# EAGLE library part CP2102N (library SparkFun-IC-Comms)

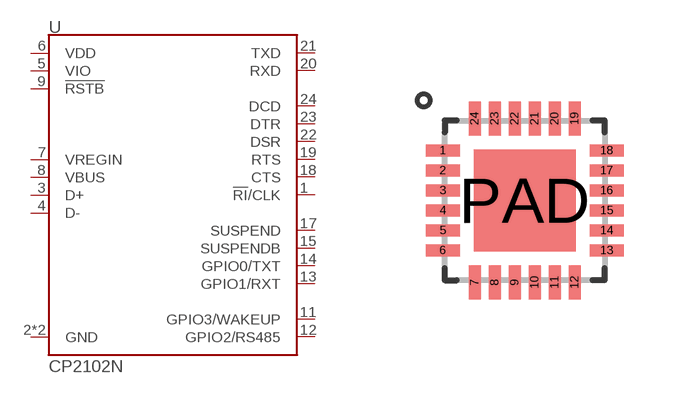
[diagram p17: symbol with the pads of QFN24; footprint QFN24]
Designator prefix U

## CP2102N (PROD_ID: IC-14020)  [QFN24]
1  !RI!/CLK
2  GND
3  D+
4  D-
5  VIO
6  VDD
7  VREGIN
8  VBUS
9  !RSTB
11  GPIO3/WAKEUP
12  GPIO2/RS485
13  GPIO1/RXT
14  GPIO0/TXT
15  SUSPENDB
17  SUSPEND
18  CTS
19  RTS
20  RXD
21  TXD
22  DSR
23  DTR
24  DCD
PAD  GND

## Footprint QFN24 (pad centres in mm)
QFN24 Package
smd 0.85 x 0.3: 1 -2.05,1.25; 2 -2.05,0.75; 3 -2.05,0.25; 4 -2.05,-0.25; 5 -2.05,-0.75; 6 -2.05,-1.25; 13 2.05,-1.25; 14 2.05,-0.75; 15 2.05,-0.25; 16 2.05,0.25; 17 2.05,0.75; 18 2.05,1.25
smd 0.3 x 0.85: 7 -1.25,-2.05; 8 -0.75,-2.05; 9 -0.25,-2.05; 10 0.25,-2.05; 11 0.75,-2.05; 12 1.25,-2.05; 19 1.25,2.05; 20 0.75,2.05; 21 0.25,2.05; 22 -0.25,2.05; 23 -0.75,2.05; 24 -1.25,2.05
smd 2.55 x 2.55: PAD 0,0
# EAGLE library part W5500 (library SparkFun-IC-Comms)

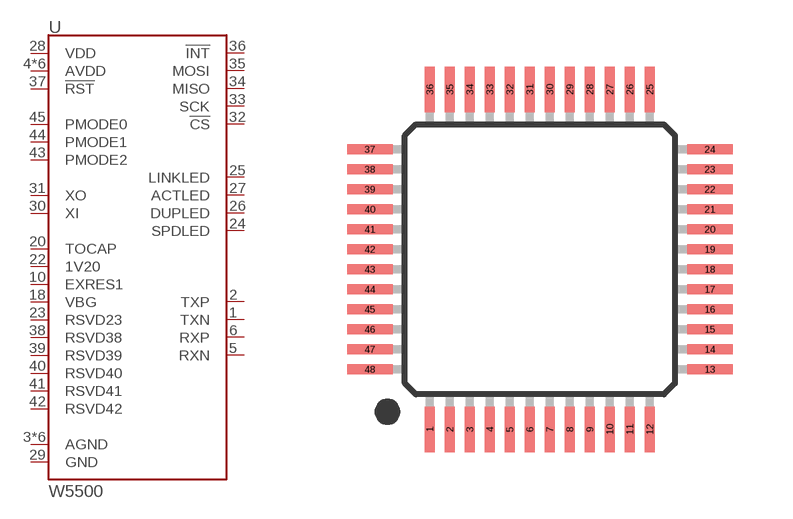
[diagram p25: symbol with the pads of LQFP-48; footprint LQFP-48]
Designator prefix U

## W5500 (PROD_ID: IC-16240)  [LQFP-48]
1  TXN
2  TXP
3  AGND
4  AVDD
5  RXN
6  RXP
8  AVDD
9  AGND
10  EXRES1
11  AVDD
14  AGND
15  AVDD
16  AGND
17  AVDD
18  VBG
19  AGND
20  TOCAP
21  AVDD
22  1V20
23  RSVD23
24  SPDLED
25  LINKLED
26  DUPLED
27  ACTLED
28  VDD
29  GND
30  XI
31  XO
32  !CS!
33  SCK
34  MISO
35  MOSI
36  !INT!
37  !RST!
38  RSVD38
39  RSVD39
40  RSVD40
41  RSVD41
42  RSVD42
43  PMODE2
44  PMODE1
45  PMODE0
48  AGND

## Footprint LQFP-48 (pad centres in mm)
LQFP -48 Specifications: Pin count: 48 Example device(s): VS1000
smd 0.254 x 1.143: 1 -2.75,-4.25; 2 -2.25,-4.25; 3 -1.75,-4.25; 4 -1.25,-4.25; 5 -0.75,-4.25; 6 -0.25,-4.25; 7 0.25,-4.25; 8 0.75,-4.25; 9 1.25,-4.25; 10 1.75,-4.25; 11 2.25,-4.25; 12 2.75,-4.25; 25 2.75,4.25; 26 2.25,4.25; 27 1.75,4.25; 28 1.25,4.25; 29 0.75,4.25; 30 0.25,4.25; 31 -0.25,4.25; 32 -0.75,4.25; 33 -1.25,4.25; 34 -1.75,4.25; 35 -2.25,4.25; 36 -2.75,4.25
smd 1.143 x 0.254: 13 4.25,-2.75; 14 4.25,-2.25; 15 4.25,-1.75; 16 4.25,-1.25; 17 4.25,-0.75; 18 4.25,-0.25; 19 4.25,0.25; 20 4.25,0.75; 21 4.25,1.25; 22 4.25,1.75; 23 4.25,2.25; 24 4.25,2.75; 37 -4.25,2.75; 38 -4.25,2.25; 39 -4.25,1.75; 40 -4.25,1.25; 41 -4.25,0.75; 42 -4.25,0.25; 43 -4.25,-0.25; 44 -4.25,-0.75; 45 -4.25,-1.25; 46 -4.25,-1.75; 47 -4.25,-2.25; 48 -4.25,-2.75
